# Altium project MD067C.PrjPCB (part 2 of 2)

## Sheet MD067C_POWER_AND_CONNECTORS.SchDoc
size 431 x 279 mm; Date: Not shown in title block; ApprovedBy: Not shown in title block; CheckedBy: Not shown in title block; Author: Not shown in title block; CompanyName: Not shown in title block; Engineer: Not shown in title block; Organization: Not shown in title block; Address1: Not shown in title block; Address2: Not shown in title block; Address3: Not shown in title block; Address4: Not shown in title block; DocumentNumber: 4; Revision: Use project parameter SCH_Rev; SheetNumber: 4; SheetTotal: 5; PageSetup: Record=PageOptions¦CenterHorizontal=True¦CenterVertical=True¦PrintScale=1.00¦XCorrection=1.00¦YCorrection=1.00¦PrintKind=0¦BorderSize=5000000¦LeftOffset=0¦BottomOffset=0¦Orientation=2¦PaperLength=1000¦PaperWidth=1000¦Scale=100¦PaperSource=15¦PrintQuality=600¦MediaType=1¦DitherType=10¦PaperKind=Letter¦PrintScaleMode=1

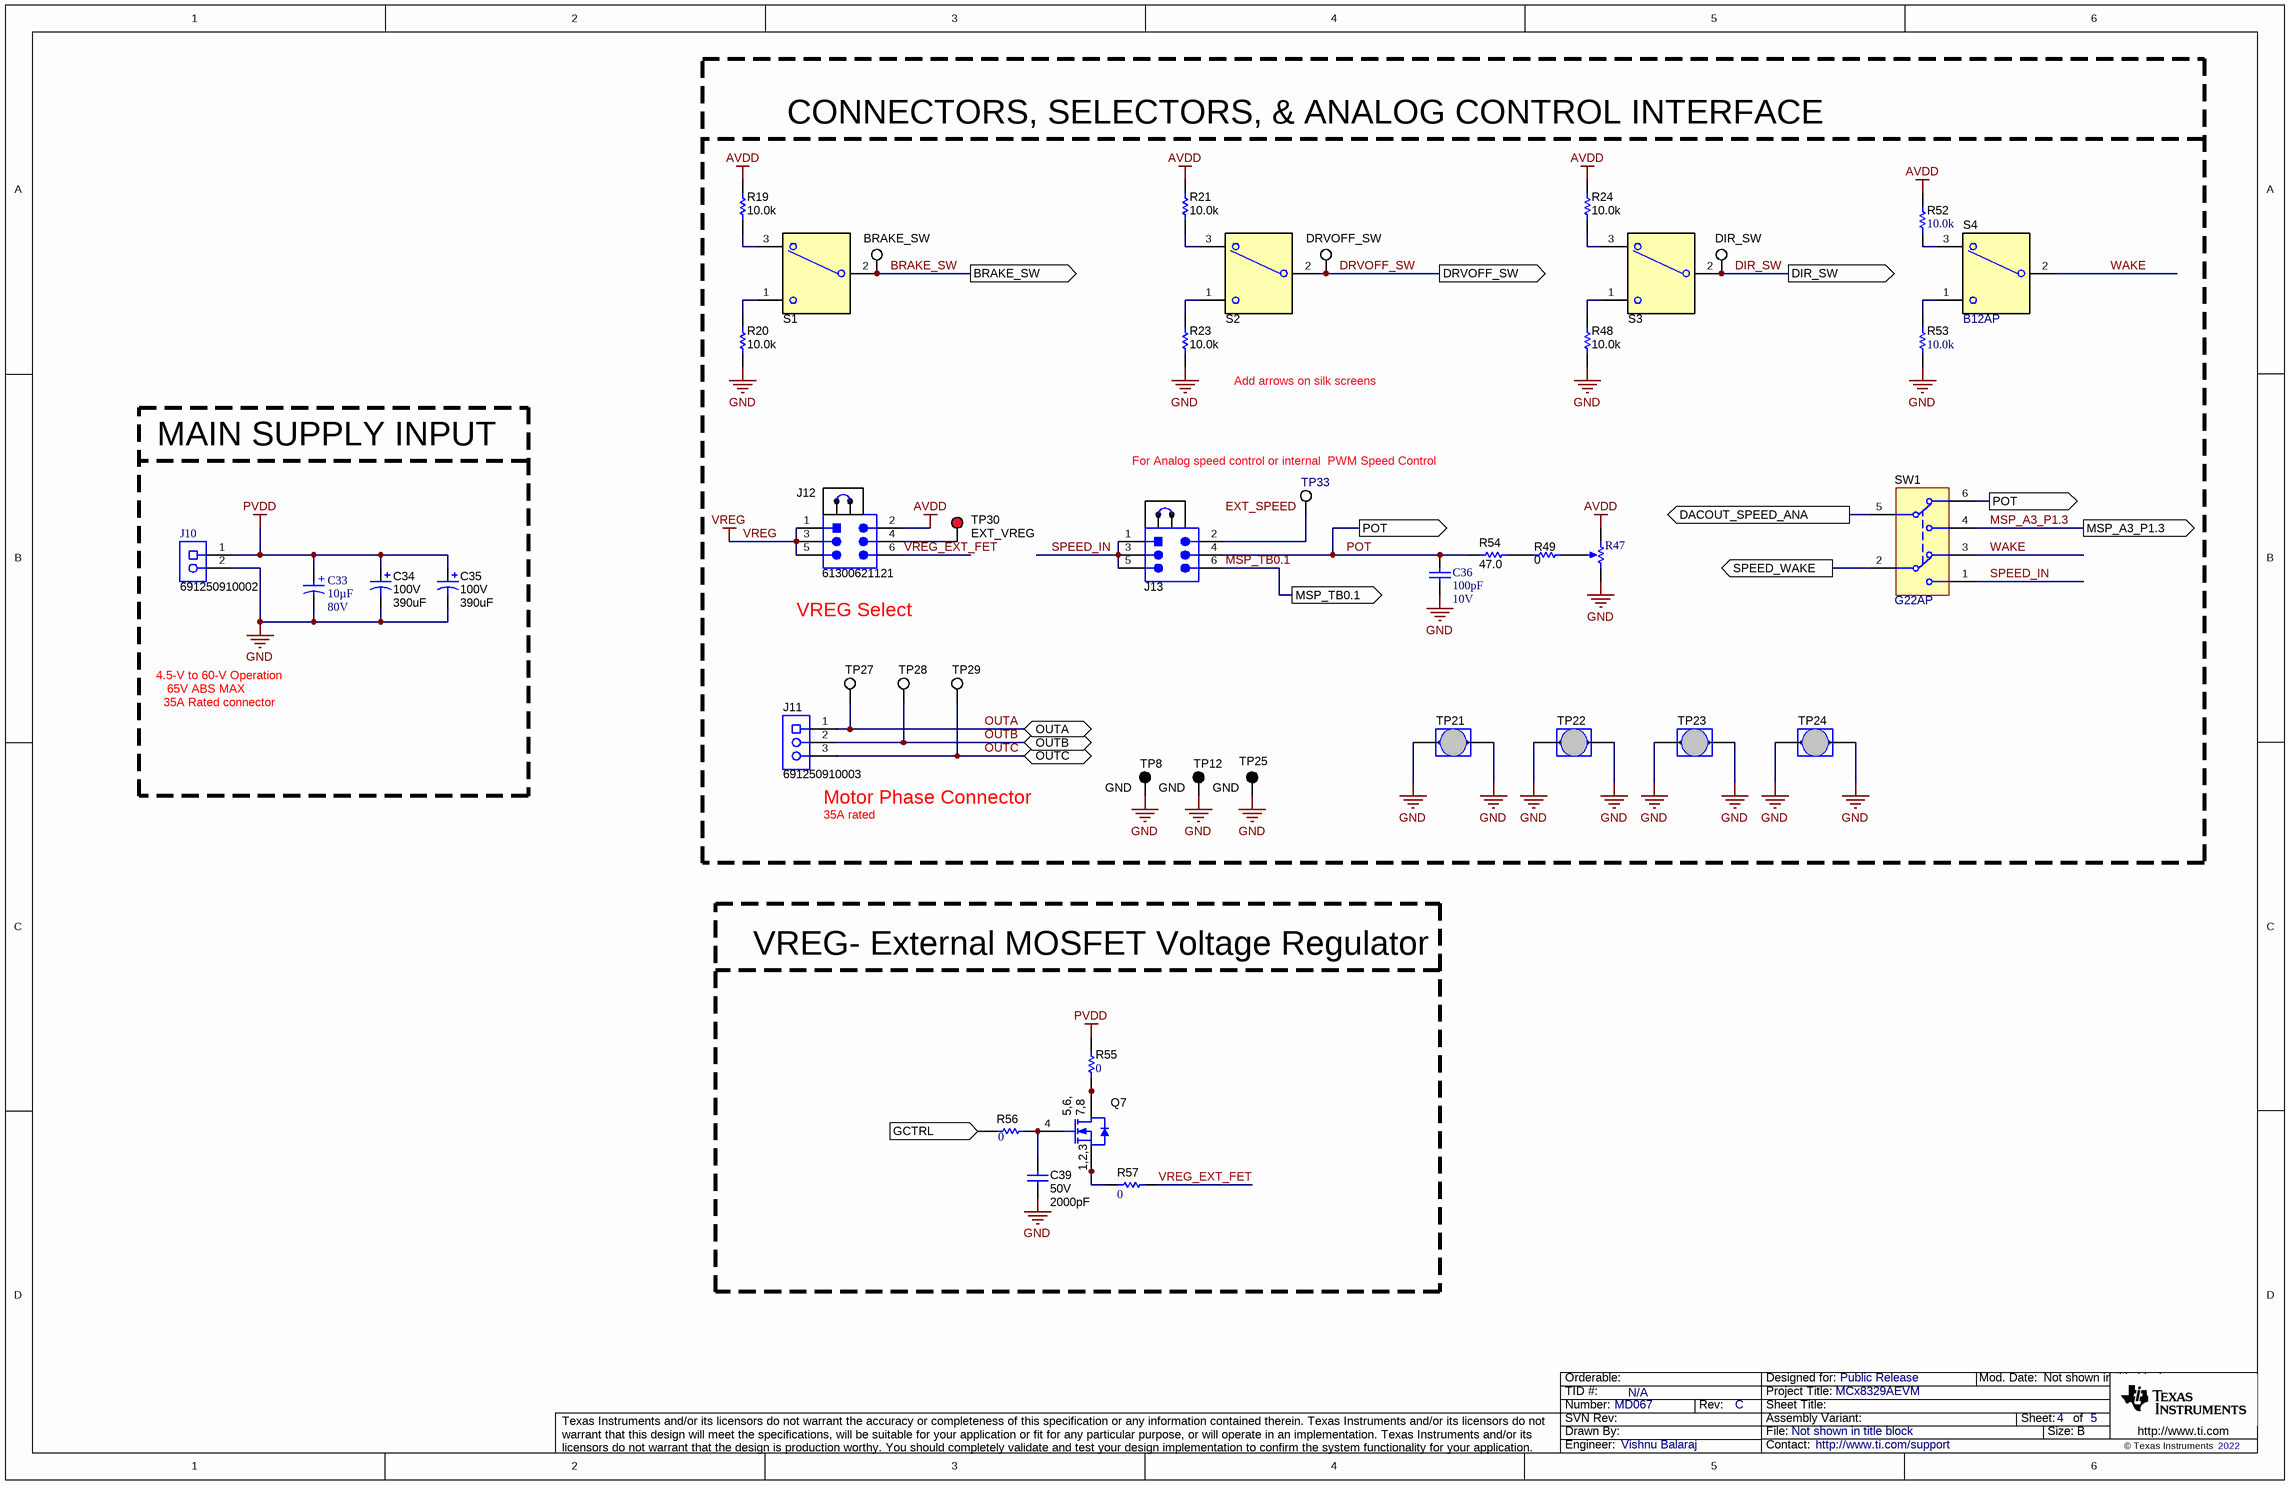
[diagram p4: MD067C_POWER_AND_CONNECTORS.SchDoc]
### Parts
C33  Cap_F: 10µF  Rated Voltage (DC): 80V  [WCAP-ASLI_D6.3H7.7]  (hidden comment: 865081745005)
C34  VDC_V: 100V  ValueDisplayed: 390uF  [KYB_1250x3500]  (hidden comment: EKYB101ELL391MK35S)
C35  VDC_V: 100V  ValueDisplayed: 390uF  [KYB_1250x3500]  (hidden comment: EKYB101ELL391MK35S)
C36  Cap_F: 100pF  Rated Voltage (DC): 10V  [WCAP-CSGP_0603_L1.6W0.8H0.8_Reflow]  (hidden comment: 885012206003)
C39  VDC_V: 50V  ValueDisplayed: 2000pF  [1206]  (hidden comment: 12065A202JAT2A)
J10  691250910002  [FP-691250910002_CONN_TERM_BLK2-MFG]
J11  691250910003  [FP-691250910003_CONN_TERM_BLK3-MFG]
J12  61300621121  [Wurth_61300621121]
J13  Header_3x2  [Wurth_61300621121]  (value not drawn)
Q7  CSD18534Q5A  [DQJ0008A]  (value not drawn)
R19  ValueDisplayed: 10.0k  [0603L]  (hidden comment: ERA-3ARW103V)
R20  ValueDisplayed: 10.0k  [0603L]  (hidden comment: ERA-3ARW103V)
R21  ValueDisplayed: 10.0k  [0603L]  (hidden comment: ERA-3ARW103V)
R23  ValueDisplayed: 10.0k  [0603L]  (hidden comment: ERA-3ARW103V)
R24  ValueDisplayed: 10.0k  [0603L]  (hidden comment: ERA-3ARW103V)
R47  3352T-1-253LF  [Bourns_3352T]  (value not drawn)
R48  ValueDisplayed: 10.0k  [0603L]  (hidden comment: ERA-3ARW103V)
R49  ValueDisplayed: 0  [0603L]  (hidden comment: ERJ-3GEY0R00V)
R52  ValueDisplayed: 10.0k  [0603]  (hidden comment: ERA-3ARW103V)
R53  ValueDisplayed: 10.0k  [0603]  (hidden comment: ERA-3ARW103V)
R54  ValueDisplayed: 47.0  [0603]  (hidden comment: RT0603BRD0747RL)
R55  ValueDisplayed: 0  [0603]  (hidden comment: ERJ-3GEY0R00V)
R56  ValueDisplayed: 0  [0603]  (hidden comment: ERJ-3GEY0R00V)
R57  ValueDisplayed: 0  [0603]  (hidden comment: ERJ-3GEY0R00V)
S1  SW_SPDT_COM2_1_3  [SW_B12AP]  (value not drawn)
S2  SW_SPDT_COM2_1_3  [SW_B12AP]  (value not drawn)
S3  SW_SPDT_COM2_1_3  [SW_B12AP]  (value not drawn)
S4  B12AP  [SW_B12AP]
SH-J7  60900213421  [Wurth_60900213421]  (value not drawn)
SH-J8  60900213421  [Wurth_60900213421]  (value not drawn)
SW1  G22AP  [SW_G2xAP]
TP8  GND  [Keystone5001]
TP12  GND  [Keystone5001]
TP21  GND  [Harwin_D3082-05]  (value not drawn)
TP22  GND  [Harwin_D3082-05]  (value not drawn)
TP23  GND  [Harwin_D3082-05]  (value not drawn)
TP24  GND  [Harwin_D3082-05]  (value not drawn)
TP25  GND  [Keystone5001]
TP26  BRAKE_SW  [Keystone5002]
TP27  OUTA  [Testpoint_Keystone_Compact]  (value not drawn)
TP28  OUTB  [Testpoint_Keystone_Compact]  (value not drawn)
TP29  OUTC  [Testpoint_Keystone_Compact]  (value not drawn)
TP30  EXT_VREG  [Keystone5000]
TP31  DRVOFF_SW  [Keystone5002]
TP32  DIR_SW  [Keystone5002]
TP33  EXT_SPEED  [Keystone5002]  (value not drawn)

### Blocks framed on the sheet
CONNECTORS, SELECTORS, & ANALOG CONTROL INTERFACE: C36 J11-J13 R19-R21 R23 R24 R47-R49 R52-R54 S1-S4 SH-J7 SH-J8 SW1 TP8 TP12 TP21-TP33
MAIN SUPPLY INPUT: C33-C35 J10
VREG- External MOSFET Voltage Regulator: C39 Q7 R55-R57

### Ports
BRAKE_SW (out), DACOUT_SPEED_ANA (out), DIR_SW (out), DRVOFF_SW (out), GCTRL (in), MSP_A3_P1.3 (out), MSP_TB0.1 (out), OUTA (bidir), OUTB (bidir), OUTC (bidir), POT (out), SPEED_WAKE (out)

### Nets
AVDD: J12.2 R19.2 R21.2 R24.2 R47.1(CCW) R52.2
GND: C33.2(N) C34.2(-) C35.2(-) C36.2 C39.2 J10.2 R20.1 R23.1 R47.3(CW) R48.1 R53.1 TP8.1 TP12.1 TP21.1 TP21.2 TP22.1 TP22.2 TP23.1 TP23.2 TP24.1 TP24.2 TP25.1
PVDD: C33.1(P) C34.1(+) C35.1(+) J10.1 R55.2
VREG: J12.1 J12.3 J12.5
BRAKE_SW: S1.2(COM) TP26.1 ; port BRAKE_SW
DACOUT_SPEED_ANA: SW1.5 ; port DACOUT_SPEED_ANA
DIR_SW: S3.2(COM) TP32.1 ; port DIR_SW
DRVOFF_SW: S2.2(COM) TP31.1 ; port DRVOFF_SW
GCTRL: R56.1 ; port GCTRL
MSP_A3_P1.3: SW1.4 ; port MSP_A3_P1.3
MSP_TB0.1: J13.6 ; port MSP_TB0.1
OUTA: J11.1 TP27.1 ; port OUTA
OUTB: J11.2 TP28.1 ; port OUTB
OUTC: J11.3 TP29.1 ; port OUTC
POT: C36.1 J13.4 R54.1 SW1.6 ; port POT
SPEED_IN: J13.1 J13.3 J13.5 SW1.1
SPEED_WAKE: SW1.2 ; port SPEED_WAKE
VREG_EXT_FET: J12.6 R57.2
WAKE: S4.2(COM) SW1.3
NetC39_1: C39.1 Q7.4(G) R56.2
NetJ12_4: J12.4 TP30.1
NetJ13_2: J13.2 TP33.1
NetQ7_1: Q7.1(S) Q7.2(S) Q7.3(S) R57.1
NetQ7_5: Q7.5(D) Q7.6(D) Q7.7(D) Q7.8(D) Q7.9(D) R55.1
NetR19_1: R19.1 S1.3
NetR20_2: R20.2 S1.1
NetR21_1: R21.1 S2.3
NetR23_2: R23.2 S2.1
NetR24_1: R24.1 S3.3
NetR47_2: R47.2(WIPER) R49.2
NetR48_2: R48.2 S3.1
NetR49_1: R49.1 R54.2
NetR52_1: R52.1 S4.3
NetR53_2: R53.2 S4.1

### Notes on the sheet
- Add arrows on silk screens
- For Analog speed control or internal  PWM Speed Control
- VREG Select
- 65V ABS MAX
- 4.5-V to 60-V Operation
- 35A Rated connector
- (near J11) Motor Phase Connector
- 35A rated
- Labels drawn without touching a wire or pin: EXT_SPEED

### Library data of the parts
C33 = CMP-0110675-1: WCAP-ASLI Aluminum Electrolytic Capacitor, V-Chip, D6.3 x H7.7mm, 10uF, 80V; Manufacturer: Wurth Elektronik; Capacitance Tolerance: +/-20%; Dissipation Factor: 10%; Endurance: 2000h; Leakage Current: 8uA; Ripple Current: 35mA; Technical Reference: ASED077100M080DVCTCB000
C34 C35 = CMP-0009875-2: CAP, AL, 390 uF, 100 V, +/- 20%, 0.026 ohm, TH; Manufacturer: Chemi-Con; TaMin_C: -40°C; ESR_ohm: 0.026; Polarized: Y; SizeAreaWB_mm2: 210.25; U/M: EA; Value: 390uF; TaMax_C: 105°C; SizeZ_mm: 36.5; SizeX_mm: 12.5; Cap_Case: 12.5x35mm; SizeArea_mm2: 156.25; CompType: Capacitor; AEC Qualified: N; Cap_F: 390µF; IRMS_A: 2.25A; AEC Category: Q200
C36 = CMP-0104643-1: WCAP-CSGP Multilayer Ceramic Chip Capacitor, General Purpose, size 0603, X7R, 100pF, 10VDC; Manufacturer: Wurth Elektronik; Capacitance Tolerance: +/-10%; Case/Size Code: 0603; Dissipation Factor: 5%; Insulation Resistance: 10GOhm; Technical Reference: X7R0603101K010DFCT10000
C39 = CMP-0082630-1: CAP, CERM, 2000 pF, 50 V,+/- 5%, C0G/NP0, 1206; Manufacturer: AVX; Cap_F: 2nF; SizeAreaWB_mm2: 10.92; SizeArea_mm2: 5.12; AEC Qualified: N; AEC Category: Q200; Value: 2000pF; TaMax_C: 125°C; SizeZ_mm: 1.35; Green_REACh: Incomplete; TaMin_C: -55°C; SizeY_mm: 1.6; Green_Lifecycle: Active; U/M: EA; SizeX_mm: 3.2
J10 = CMP-0121275-2: 2 Position Wire to Board Terminal Block Horizontal with Board 0.375" (9.53mm) Through Hole; Manufacturer: Wurth Electronics; Current_A: 24A; Voltage_V: 300V; Row_Count: 1; AEC Qualified: No; Conn Gender: Female; DUT-Pitch_mm: 9.52mm; Is Female: yes; Max Wire Gauge: 10; Min Wire Gauge: 30; SizeZ_mm: 21.6mm
J11 = CMP-0121276-2: 3 Position Wire to Board Terminal Block Horizontal with Board 0.375" (9.53mm) Through Hole; Manufacturer: Wurth Electronics; Current_A: 24A; Voltage_V: 300V; Row_Count: 1; AEC Qualified: No; Conn Gender: Female; DUT-Pitch_mm: 9.52mm; Is Female: yes; Max Wire Gauge: 10; Min Wire Gauge: 30; SizeZ_mm: 21.6mm
J12 = CMP-0054802-2: Header, 2.54mm, 3x2, Gold, TH; Manufacturer: Wurth Elektronik; Pitch_mm: 2.54; Gender: Male; Green_REACh: Passed; Shrouded: N; Green_Lifecycle: Active; Row_Count: 2
J13 = CMP-0054802-2: Header, 2.54mm, 3x2, Gold, TH; PartNumber: 61300621121; Manufacturer: Wurth Elektronik; Pitch_mm: 2.54; Gender: Male; Shrouded: N; Row_Count: 2; Green_Lifecycle: Active; Green_REACh: Passed
Q7 = CMP-0000817-1: MOSFET, N-CH, 60 V, 50 A, DQJ0008A (VSONP-8); Alternate Manufacturer: None; Manufacturer: Texas Instruments; SizeZ_mm: 1.1; ChType: N; Value2: 22 nC; Value1: 0.009; VdsMax_V: 60V; SizeX_mm: 6; SizeY_mm: 4.9; Vgs_V: 2.3V; Value: 60V; Rdson45_ohm: 9.8m; SizeArea_mm2: 29.4; AEC Category: Q101; IdsMax_A: 50A; SizeAreaWB_mm2: 55.2; U/M: EA; QgTyp_nC: 22
R19-R21 R23 R24 R48 R52 R53 = CMP-0086251-1: RES, 10.0 k, 0.05%, 0.1 W, AEC-Q200 Grade 0, 0603; Manufacturer: Panasonic; Res_ohm: 10k; Value: 10.0k; SizeY_mm: 0.8; SizeArea_mm2: 1.28; SizeAreaWB_mm2: 4.68; AEC Grade: 0; Power_W: 100mW; SizeX_mm: 1.6; Value2: 0.1W; Value_Code: 10k0; SizeZ_mm: 1; AEC Qualified: Y; AEC Category: Q200; TempCo: 10 ppm/C
R47 = CMP-0001776-2: Trimmer Potentiometer, 25kohm, 0.5W, TH; Manufacturer: Bourns
R49 R55-R57 = CMP-0025874-4: RES, 0, 5%, 0.1 W, AEC-Q200 Grade 0, 0603; Manufacturer: Panasonic; Power_W: 100mW; TempCo: 600 ppm/C; Value_Code: 0000; Value: 0; EIA_Code: E24; SizeX_mm: 1.6; SizeY_mm: 0.8; SizeZ_mm: 1; Value2: 0.1W; SizeArea_mm2: 1.28; AEC Qualified: Y; VDC_V: 50V; AEC Category: Q200; SizeAreaWB_mm2: 4.68
R54 = CMP-0024269-1: RES, 47.0, 0.1%, 0.1 W, 0603; Manufacturer: Yageo America; Power_W: 100mW; TempCo: 25 ppm/C; Value_Code: 47R0; U/M: EA; Value: 47.0; EIA_Code: E192; Res_ohm: 47; SizeX_mm: 1.6; SizeY_mm: 0.8; SizeZ_mm: 1; Value2: 0.1W; SizeArea_mm2: 1.28; VDC_V: 75V; AEC Category: Q200
S1-S3 = CMP-0002155-2: SWITCH TOGGLE SPDT 0.4VA 28V; PartNumber: B12AP; Manufacturer: NKK Switches; SwitchFunction: On-On; PositionCount: 2; CurrentRating_mA: 100A
S4 = CMP-0002155-2: SWITCH TOGGLE SPDT 0.4VA 28V; Manufacturer: NKK Switches; CurrentRating_mA: 100A; PositionCount: 2; SwitchFunction: On-On
SH-J7 SH-J8 = CMP-0003761-2: Shunt, 2.54mm, Gold, Black; Manufacturer: Wurth Elektronik; Value: 1x2
SW1 = CMP-0002204-1: Switch, DPDT, On-On, 0.4 VA, 28 V, TH; Manufacturer: NKK Switches; CurrentRating_mA: 400A; PositionCount: 2; VDC_V: 28V
TP8 TP12 TP25 = CMP-0055138-1: Test Point, Miniature, Black, TH; Manufacturer: Keystone; CNHeader: FALSE; Green_Lifecycle: Active; Green_REACh: Passed; ContactFinish: Silver; CT: TRUE
TP21-TP24 = CMP-0075110-1: 1mm Uninsulated Shorting Plug, 10.16mm spacing, TH; Manufacturer: Harwin; PartNumber: D3082-05; CNHeader: False; Green_Lifecycle: Active; Green_REACh: Passed; CompType: Jumper Wire
TP26 TP31-TP33 = CMP-0055139-1: Test Point, Miniature, White, TH; Manufacturer: Keystone; CNHeader: FALSE; Green_Lifecycle: Active; Green_REACh: Passed; ContactFinish: Silver; CT: TRUE
TP27-TP29 = CMP-0055153-1: Test Point, Compact, SMT; Manufacturer: Keystone; CNHeader: FALSE; Green_Lifecycle: Active; Green_REACh: Passed; CT: TRUE
TP30 = CMP-0055137-1: Test Point, Miniature, Red, TH; PartNumber: 5000; Manufacturer: Keystone; ContactFinish: Silver; CNHeader: FALSE; CT: TRUE; Green_Lifecycle: Active; Green_REACh: Passed

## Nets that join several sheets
AVDD: MD067C_DRIVER (10 pins), MD067C_POWER_AND_CONNECTORS (6 pins)
GND: MD067C_DRIVER (23 pins), MD067C_FETS_AND_POWER_STAGE (7 pins), MD067C_INTERFACE (25 pins), MD067C_POWER_AND_CONNECTORS (22 pins)
LSS: MD067C_DRIVER (J4.14 TP9.1 U1.21), MD067C_FETS_AND_POWER_STAGE (17 pins)
PVDD: MD067C_DRIVER (5 pins), MD067C_FETS_AND_POWER_STAGE (12 pins), MD067C_POWER_AND_CONNECTORS (5 pins)
VREG: MD067C_DRIVER (C37.2 C38.1 U1.2), MD067C_POWER_AND_CONNECTORS (J12.1 J12.3 J12.5)
BRAKE: MD067C_DRIVER (U1.34), MD067C_INTERFACE (J9.27)
BRAKE_SW: MD067C_INTERFACE (J9.28), MD067C_POWER_AND_CONNECTORS (S1.2 TP26.1)
DACOUT/SOX/SPEED_ANA: MD067C_DRIVER (R3.1 TP2.1 U1.33), MD067C_INTERFACE (J9.15)
DACOUT_SPEED_ANA: MD067C_INTERFACE (J9.16), MD067C_POWER_AND_CONNECTORS (SW1.5)
DIR: MD067C_DRIVER (R6.1 U1.31), MD067C_INTERFACE (J9.29)
DIR_SW: MD067C_INTERFACE (J9.30), MD067C_POWER_AND_CONNECTORS (S3.2 TP32.1)
DRVOFF: MD067C_DRIVER (U1.24), MD067C_INTERFACE (J9.31)
DRVOFF_SW: MD067C_INTERFACE (J9.32), MD067C_POWER_AND_CONNECTORS (S2.2 TP31.1)
FGOUT: MD067C_DRIVER (R8.1 TP4.1 U1.28), MD067C_INTERFACE (J9.5)
GCTRL: MD067C_DRIVER (TP5.1 U1.3), MD067C_POWER_AND_CONNECTORS (R56.1)
GHA: MD067C_DRIVER (J4.4 U1.11), MD067C_FETS_AND_POWER_STAGE (R28.1 R31.1)
GHB: MD067C_DRIVER (J4.8 U1.15), MD067C_FETS_AND_POWER_STAGE (R29.1 R32.1)
GHC: MD067C_DRIVER (J4.12 U1.19), MD067C_FETS_AND_POWER_STAGE (R30.1 R33.1)
GLA: MD067C_DRIVER (J4.5 U1.12), MD067C_FETS_AND_POWER_STAGE (R34.1 R37.1)
GLB: MD067C_DRIVER (J4.9 U1.16), MD067C_FETS_AND_POWER_STAGE (R35.1 R38.1)
GLC: MD067C_DRIVER (J4.13 U1.20), MD067C_FETS_AND_POWER_STAGE (R36.1 R39.1)
MCX_SCL: MD067C_DRIVER (R9.1 R11.1), MD067C_INTERFACE (J9.23)
MCX_SDA: MD067C_DRIVER (R10.1 R12.1), MD067C_INTERFACE (J9.21)
MSP_A3_P1.3: MD067C_INTERFACE (U5.48), MD067C_POWER_AND_CONNECTORS (SW1.4)
MSP_TB0.1: MD067C_INTERFACE (U5.42), MD067C_POWER_AND_CONNECTORS (J13.6)
nFAULT: MD067C_DRIVER (R5.1 R7.2 R14.1 U1.35), MD067C_INTERFACE (J9.7)
OUTA: MD067C_FETS_AND_POWER_STAGE (7 pins), MD067C_POWER_AND_CONNECTORS (J11.1 TP27.1)
OUTB: MD067C_FETS_AND_POWER_STAGE (7 pins), MD067C_POWER_AND_CONNECTORS (J11.2 TP28.1)
OUTC: MD067C_FETS_AND_POWER_STAGE (7 pins), MD067C_POWER_AND_CONNECTORS (J11.3 TP29.1)
POT: MD067C_INTERFACE (U5.43), MD067C_POWER_AND_CONNECTORS (C36.1 J13.4 R54.1 SW1.6)
SHA: MD067C_DRIVER (C8.2 J4.3 U1.10), MD067C_FETS_AND_POWER_STAGE (NT1.1)
SHB: MD067C_DRIVER (C9.1 J4.7 U1.14), MD067C_FETS_AND_POWER_STAGE (NT2.1)
SHC: MD067C_DRIVER (C10.1 J4.11 U1.18), MD067C_FETS_AND_POWER_STAGE (NT3.1)
SN: MD067C_DRIVER (TP39.1 U1.23), MD067C_FETS_AND_POWER_STAGE (C31.2 C32.1 R45.1)
SP: MD067C_DRIVER (TP11.1 U1.22), MD067C_FETS_AND_POWER_STAGE (C30.2 C31.1 R43.1)
SPEED/WAKE: MD067C_DRIVER (R51.2 U1.27), MD067C_INTERFACE (J9.25)
SPEED_WAKE: MD067C_INTERFACE (J9.26), MD067C_POWER_AND_CONNECTORS (SW1.2)

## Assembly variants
001: not fitted C12 C13 C14 C15 C17 C19 C24 C25 C26 C27 C28 C29 C30 C31 C32 D5 D6 D7 D8 D9 D10 FID1 FID2 FID3 R1 R2 R3 R4 R5 R6 R22 R25 R26 R27 R31 R32 R33 R37 R38 R39 R40 R41 R42 R50 R51 R56 R60 R75 R76 R77 R78
002: not fitted C12 C13 C14 C15 C17 C19 C24 C25 C26 C27 C28 C29 C30 C31 C32 D5 D6 D7 D8 D9 D10 FID1 FID2 FID3 R1 R2 R3 R4 R5 R6 R22 R25 R26 R27 R31 R32 R33 R37 R38 R39 R40 R41 R42 R50 R51 R56 R60 R75 R76 R77 R78; alternate parts U1 -> CMP-0036720-2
